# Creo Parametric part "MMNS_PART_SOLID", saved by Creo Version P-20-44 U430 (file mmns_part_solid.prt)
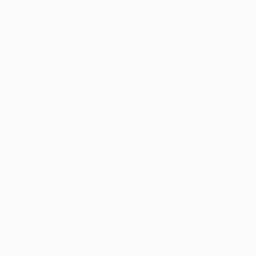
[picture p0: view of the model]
Units: millimeter Newton Second (mmNs); MM, TONNE, SECS

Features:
  1. datum plane "RIGHT"
  2. datum plane "TOP"
  3. datum plane "FRONT"
  4. coordinate system

Surfaces: 3 plane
